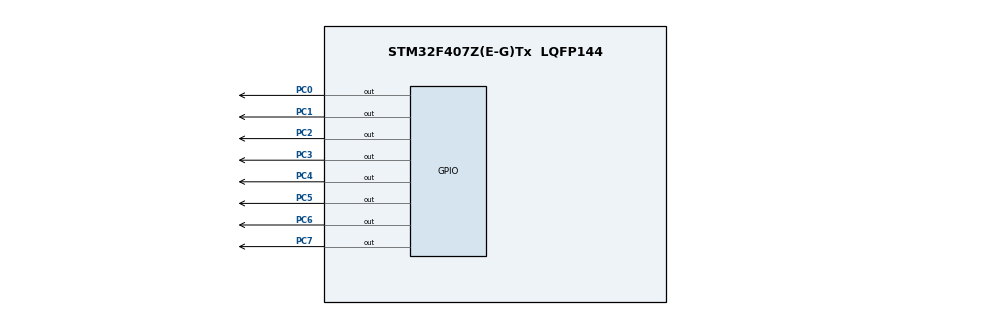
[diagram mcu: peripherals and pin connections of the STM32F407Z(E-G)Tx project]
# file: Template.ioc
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Mcu.Family=STM32F4
Mcu.Name=STM32F407Z(E-G)Tx
Mcu.Package=LQFP144
NVIC.PriorityGroup=NVIC_PRIORITYGROUP_4
PC0.Signal=GPIO_Output
PC1.Signal=GPIO_Output
PC2.Signal=GPIO_Output
PC3.Signal=GPIO_Output
PC4.Signal=GPIO_Output
PC5.Signal=GPIO_Output
PC6.Signal=GPIO_Output
PC7.Signal=GPIO_Output
ProjectManager.HeapSize=0x200
ProjectManager.StackSize=0x400
ProjectManager.TargetToolchain=EWARM V8.50
RCC.AHBFreq_Value=16000000
RCC.APB1Freq_Value=16000000
RCC.APB2Freq_Value=16000000
RCC.CortexFreq_Value=16000000
RCC.HSE_VALUE=25000000
RCC.HSI_VALUE=16000000
RCC.LSE_VALUE=32768
RCC.SYSCLKFreq_VALUE=16000000
RCC.VCOOutputFreq_Value=192000000
board=custom

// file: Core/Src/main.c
/* USER CODE BEGIN Header */
/**
  ******************************************************************************
  * @file           : main.c
  * @brief          : Main program body
  ******************************************************************************
  * @attention
  *
  * Copyright (c) 2025 STMicroelectronics.
  * All rights reserved.
  *
  * This software is licensed under terms that can be found in the LICENSE file
  * in the root directory of this software component.
  * If no LICENSE file comes with this software, it is provided AS-IS.
  *
  ******************************************************************************
  */
/* USER CODE END Header */
#include "main.h"
#include "oled.h"
/* USER CODE BEGIN Includes */
#include "oled.h"
/* USER CODE END Includes */

void SystemClock_Config(void);

int main(void)
{

  /* MCU Configuration--------------------------------------------------------*/

  /* Reset of all peripherals, Initializes the Flash interface and the Systick. */
  HAL_Init();

  /* Configure the system clock */
  SystemClock_Config();

  /* Initialize all configured peripherals */

  /* Infinite loop */
  while (1)
  {
  OLED_ShowString(1, 3, "HelloWorld!");
	  OLED_ShowCharacter(1, 11, 'A');
	   	uint32_t n=365;
		 OLED_ShowInteger(2, 1, n,4);

  }
}

void SystemClock_Config(void)
{
  RCC_OscInitTypeDef RCC_OscInitStruct = {0};
  RCC_ClkInitTypeDef RCC_ClkInitStruct = {0};

  /** Configure the main internal regulator output voltage
  */
  __HAL_RCC_PWR_CLK_ENABLE();
  __HAL_PWR_VOLTAGESCALING_CONFIG(PWR_REGULATOR_VOLTAGE_SCALE1);

  /** Initializes the RCC Oscillators according to the specified parameters
  * in the RCC_OscInitTypeDef structure.
  */
  RCC_OscInitStruct.OscillatorType = RCC_OSCILLATORTYPE_HSE;
  RCC_OscInitStruct.HSEState = RCC_HSE_ON;
  RCC_OscInitStruct.PLL.PLLState = RCC_PLL_ON;
  RCC_OscInitStruct.PLL.PLLSource = RCC_PLLSOURCE_HSE;
  RCC_OscInitStruct.PLL.PLLM = 4;
  RCC_OscInitStruct.PLL.PLLN = 168;
  RCC_OscInitStruct.PLL.PLLP = RCC_PLLP_DIV2;
  RCC_OscInitStruct.PLL.PLLQ = 4;
  if (HAL_RCC_OscConfig(&RCC_OscInitStruct) != HAL_OK)
  {
    Error_Handler();
  }

  /** Initializes the CPU, AHB and APB buses clocks
  */
  RCC_ClkInitStruct.ClockType = RCC_CLOCKTYPE_HCLK|RCC_CLOCKTYPE_SYSCLK
                              |RCC_CLOCKTYPE_PCLK1|RCC_CLOCKTYPE_PCLK2;
  RCC_ClkInitStruct.SYSCLKSource = RCC_SYSCLKSOURCE_PLLCLK;
  RCC_ClkInitStruct.AHBCLKDivider = RCC_SYSCLK_DIV1;
  RCC_ClkInitStruct.APB1CLKDivider = RCC_HCLK_DIV4;
  RCC_ClkInitStruct.APB2CLKDivider = RCC_HCLK_DIV2;

  if (HAL_RCC_ClockConfig(&RCC_ClkInitStruct, FLASH_LATENCY_5) != HAL_OK)
  {
    Error_Handler();
  }
}

void Error_Handler(void)
{
  __disable_irq();
  while (1)
  {
  }
}
